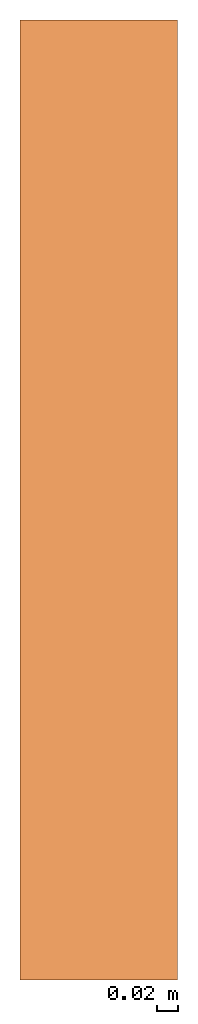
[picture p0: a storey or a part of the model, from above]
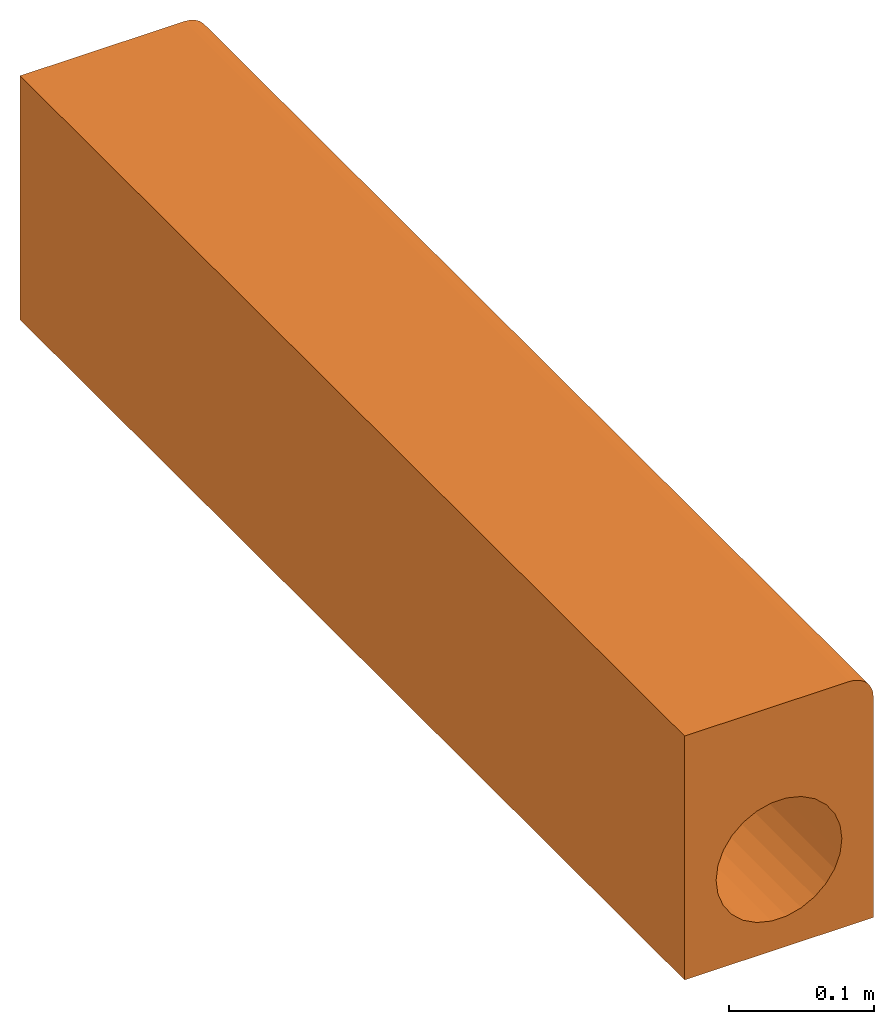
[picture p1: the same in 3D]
Properties of the parts of a building model (IFC2X3)

# File
Description: ViewDefinition [CoordinationView]
File name: 7965 - Centre stone - 915mm LG.ifc
Time: 2013-09-12T12:44:26
Written by: Autodesk Revit 2013
Made in: 20120221_2030(x64)

# IfcProject, Project Number
LongName: Project Name; Phase: Project Status

# IfcSite, Default
RefLatitude: 42, 21, 30, 344238; RefLongitude: -71, -3, -35, -194702; RefElevation: 0 mm

# IfcBuilding
Pset_BuildingCommon - NumberOfStoreys: 2
Other - Project Issue Date: Issue Date; Project Status: Project Status; Project Number: Project Number; Project Name: Project Name; Project Address: Enter address here; Client Name: Owner

# IfcBuildingStorey (2)
Constraints - Elevation Base: 0
Graphics - Line Pattern: Center; Symbol at End 1 Default: no; Symbol at End 2 Default: yes; Line Weight: 1; Color: 0; Symbol: M_Level Head - Circle: M_Level Head - Circle
Identity Data - Structural: no; Building Story: yes
Dimensions - Computation Height: 0 mm
Name | LongName = Name | Elevation (mm) = Constraints, Elevation (mm)
T.O. Fnd. Wall | T.O. Fnd. Wall | -300
Level 1 | Level 1 | 0

# IfcBuildingElementProxy: 7965 - Centre stone - 915mm LG, Civil-Drainage-Channel-ACO-KerbDrain-HB305 - PART 1:7965 - Centre stone - 915mm LG:7965 - Centre stone - 915mm LG:255899
In: T.O. Fnd. Wall
Material: ACO Polymer Concrete.
Dimensions - Void_Width: 150 mm; I/O Endcap Void depth: 6000 mm; Void_Length: 915 mm; Staright Void Depth: -180 mm; Volume: 20879567 mm3
Other - Revision: 1; CreatedBy: www.aco.co.uk
Constraints - Level: Level: Level 1; Moves With Nearby Elements: no
Phasing - Phase Created: Phase 1
Pset_BuildingElementProxyCommon - Reference: 7965 - Centre stone - 915mm LG
General - SerialNumber: 0.000000; TagNumber: 0.000000
Green Building Properties - End Cap Recycled Material Content: N/A; Channel Recycled Material Content: 20% minimum; Access Cover/Frame Recycled Material Content: N/A; Channel Recyclable: Fully recyclable; End Cap Recyclable: N/A N/A; Access Cover/Frame Recyclable: N/A
Identity Data - Cost: 0; Address: ACO Business Park, Hitchin Road, Shefford, Bedfordshire, United Kingdom SG17 5TE; Product Page URL: http://www.aco.co.uk/product_detail.php?id=3; Model Description: Combined kerb and drainage system; Model: ACO KerbDrain HB305; OmniClass Title: Rainwater Removal; E-mail Sales: customersupport@aco.co.uk; Installation guidelines: http://www.aco.co.uk/download.php?id=120; Product Code: 7965; OmniClass Number: 23.70.50.24; Fax: +44 (0)1462 815895; E-mail Technical: technical@aco.co.uk; Telephone: +44 (0)1462 816666; URL: www.aco.co.uk; Type Comments: ACO KerbDrain HB305 half battered centre stone unit c/w 25mm upstand 915mm long; Assembly Code: D2040; Manufacturer: ACO Technologies plc - ACO Water Management Division; Assembly Description: Rain Water Drainage; Maintenance guidelines: http://www.aco.co.uk/download.php?id=120; Product brochure: http://www.aco.co.uk/download.php?id=120; Price: POA - contact ACO
Construction - I/O Pipe: no; KDHB305 - Channel unit - 250mm: no; KDHB305 - Flush RH dropkerb: no; KDHB305 - LH Inlet/Outlet end cap: no; KDHB305 - Access Unit: no; KDHB305 - Blind unit: no; KDHB305 - RH Inlet/outlet end cap: no; KDHB305 - Channel unit - 1000mm: no; KDHB305 - LH drop kerb: no; KDHB305 - Drainable centre stone: no; KDHB305 - RH drop kerb: no; KDHB305 - Closing end cap: no; KDHB305 - Channel unit - 500mm: no; KDHB305 - Flush LH dropkerb: no; KDHB305 - Perforated centre stone: no; KDHB305 - Centre stone: yes
Data - Product Weight: 43.5 Kg; Concrete Surround Volume - Load Class A 15 - D 400 - Grass or Asphalt Pavement: N/A; Concrete Surround Volume - Load Class A 15 - D 400 - Concrete Pavement: N/A; Load Class: A 15 - D 400; Drainage Slot Intake area: N/A; Drainage Slot Width: N/A; Product Dimensions: 915mm x 150mm x 205mm (LxWxH); Installation - Concrete Grade: Refer to brochure; Hydraulic Performance: http://www.aco.co.uk/download.php?id=120; Product Standard: BS EN 1433:2002, CE marked, Kitemarked; Connection Pipe O.D: N/A; ACO Hydraulic Design Software: http://www.acodesign.co.uk; Invert Depth: 180mm; Channel C.S.A: 0.008mm²
Materials and Finishes - Access Cover/Frame Colour: N/A; End Cap Colour: N/A; End Cap Material: N/A; Access Cover/Frame Finish: N/A; Channel Colour: Grey; Connection Pipe Material: N/A; Connection Pipe Material Colour: N/A; Channel Material: Vienite® Synthetic Resin Concrete; Access Cover/Frame Material: N/A

# IfcOpeningElement: Recess (2)
In: Level 1
Dimensions - Volume: 21181727206 mm3; Perimeter: 29157.2 mm; Thickness: 400 mm; Area: 53016081 mm2
Structural - Enable Analytical Model: no; Structural: no
Constraints - Room Bounding: yes; Related to Mass: no; Height Offset From Level: 0 mm; Level: Level: Level 1
Phasing - Phase Created: Phase 1
Graphics - Coarse Scale Fill Color: 0
Construction - Default Thickness: 400 mm; Function: 0
Analytical Properties - Absorptance: 0.1; Roughness: 1

# IfcSlab: Floor:Generic Floor - 400mm, Floor:Generic Floor - 400mm:184025
In: Level 1
PredefinedType: FLOOR; Material: Default Floor 400 mm
Dimensions - Volume: 21181727206 mm3; Perimeter: 29157.2 mm; Thickness: 400 mm; Area: 53016081 mm2
Structural - Enable Analytical Model: no; Structural: no
Constraints - Room Bounding: yes; Related to Mass: no; Height Offset From Level: 0 mm; Level: Level: Level 1
Phasing - Phase Created: Phase 1
Pset_SlabCommon - Reference: Generic Floor - 400mm; IsExternal: no; LoadBearing: yes
Graphics - Coarse Scale Fill Color: 0
Construction - Default Thickness: 400 mm; Function: 0
Analytical Properties - Absorptance: 0.1; Roughness: 1
